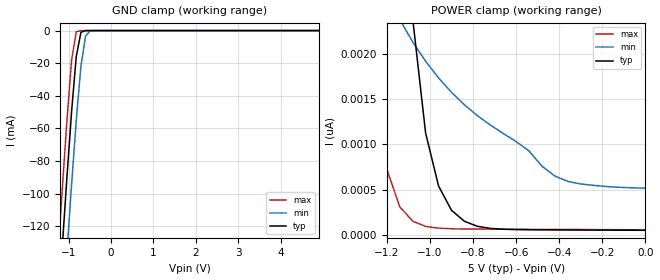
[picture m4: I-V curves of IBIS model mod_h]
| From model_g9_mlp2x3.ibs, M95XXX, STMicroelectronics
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|   Model mod_h
[Model]   mod_h
Model_type Input
Vinl   =   1.500V
Vinh   =   3.500V
C_comp   2.120pF   2.024pF   2.323pF
[Temperature Range]  25.0000   0.1050k   -40.0000
[Voltage Range]   5.0000V   4.5000V   5.5000V
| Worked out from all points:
|   GND clamp passes 1 mA (typ) near -0.70 V on its own axis
[GND_clamp]
|Voltage   I(typ)   I(min)   I(max)
-5V       -1.764A    -1.807A    -1.733A
-1.26V    -176.7mA   -223.6mA   -141.2mA
-1.15V    -132.7mA   -179.4mA   -97.27mA
-1.04V    -89.88mA   -136.2mA   -55.14mA
-930mV    -49.58mA   -94.31mA   -18.16mA
-820mV    -15.87mA   -55.06mA   -757uA
-710mV    -1.068mA   -21.8mA    -5.45uA
-600mV    -23.1uA    -3.301mA   -36.27nA
-490mV    -459.2nA   -183.8uA   -242.2pA
4.9V      10.56pA    379.5pA    10.13pA
[POWER_clamp]
|Voltage   I(typ)   I(min)   I(max)
-4.98V    28.69uA    25.8uA     31.84uA
-1.32V    46.21nA    3.573nA    4.583nA
-1.26V    23nA       3.036nA    1.802nA
-1.2V     11.01nA    2.671nA    725.9pA
-1.14V    5.144nA    2.378nA    310.5pA
-1.08V    2.39nA     2.131nA    152.3pA
-1.02V    1.125nA    1.918nA    93.17pA
-960mV    540.6pA    1.734nA    74.33pA
-900mV    272.4pA    1.575nA    67.75pA
-780mV    95.14pA    1.317nA    64.31pA
-420mV    55.03pA    648.9pA    60.42pA
0V        50.61pA    515.3pA    56pA
